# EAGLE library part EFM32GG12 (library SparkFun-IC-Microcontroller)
SiLabs EFM32GG12 Energy efficient MCU. Used as a Segger debugger chip on some products. 93 GPIO pins 32-bit ARM Cortex-M4 processor 1MB Flash memory 192kB internal RAM Datasheet

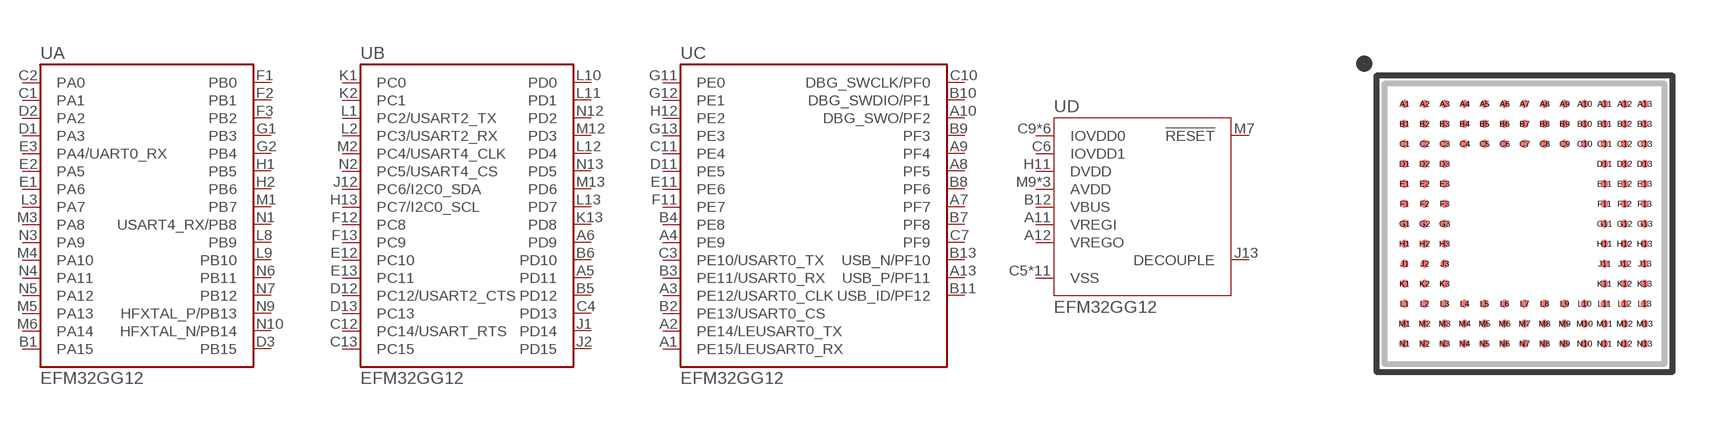
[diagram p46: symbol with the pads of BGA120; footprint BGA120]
Designator prefix U; gates A=EFM32GG12_A B=EFM32GG12_B C=EFM32GG12_C D=EFM32GG12_D

## EFM32GG12B410F1024GL120 (PROD_ID: IC-16889)  [BGA120]
A1  C:PE15/LEUSART0_RX
A2  C:PE14/LEUSART0_TX
A3  C:PE12/USART0_CLK
A4  C:PE9
A5  B:PD11
A6  B:PD9
A7  C:PF7
A8  C:PF5
A9  C:PF4
A10  C:DBG_SWO/PF2
A11  D:VREGI
A12  D:VREGO
A13  C:USB_P/PF11
B1  A:PA15
B2  C:PE13/USART0_CS
B3  C:PE11/USART0_RX
B4  C:PE8
B5  B:PD12
B6  B:PD10
B7  C:PF8
B8  C:PF6
B9  C:PF3
B10  C:DBG_SWDIO/PF1
B11  C:USB_ID/PF12
B12  D:VBUS
B13  C:USB_N/PF10
C1  A:PA1
C2  A:PA0
C3  C:PE10/USART0_TX
C4  B:PD13
C5  D:VSS
C6  D:IOVDD1
C7  C:PF9
C8  D:VSS
C9  D:IOVDD0
C10  C:DBG_SWCLK/PF0
C11  C:PE4
C12  B:PC14/USART_RTS
C13  B:PC15
D1  A:PA3
D2  A:PA2
D3  A:PB15
D11  C:PE5
D12  B:PC12/USART2_CTS
D13  B:PC13
E1  A:PA6
E2  A:PA5
E3  A:PA4/UART0_RX
E11  C:PE6
E12  B:PC10
E13  B:PC11
F1  A:PB0
F2  A:PB1
F3  A:PB2
F11  C:PE7
F12  B:PC8
F13  B:PC9
G1  A:PB3
G2  A:PB4
G3  D:IOVDD0
G11  C:PE0
G12  C:PE1
G13  C:PE3
H1  A:PB5
H2  A:PB6
H3  D:VSS
H11  D:DVDD
H12  C:PE2
H13  B:PC7/I2C0_SCL
J1  B:PD14
J2  B:PD15
J3  D:VSS
J11  D:IOVDD0
J12  B:PC6/I2C0_SDA
J13  D:DECOUPLE
K1  B:PC0
K2  B:PC1
K3  D:IOVDD0
K11  D:VSS
K12  D:VSS
K13  B:PD8
L1  B:PC2/USART2_TX
L2  B:PC3/USART2_RX
L3  A:PA7
L4  D:IOVDD0
L5  D:VSS
L6  D:VSS
L7  D:IOVDD0
L8  A:PB9
L9  A:PB10
L10  B:PD0
L11  B:PD1
L12  B:PD4
L13  B:PD7
M1  A:PB7
M2  B:PC4/USART4_CLK
M3  A:PA8
M4  A:PA10
M5  A:PA13
M6  A:PA14
M7  D:!RESET!
M8  D:VSS
M9  D:AVDD
M10  D:AVDD
M11  D:VSS
M12  B:PD3
M13  B:PD6
N1  A:USART4_RX/PB8
N2  B:PC5/USART4_CS
N3  A:PA9
N4  A:PA11
N5  A:PA12
N6  A:PB11
N7  A:PB12
N8  D:VSS
N9  A:HFXTAL_P/PB13
N10  A:HFXTAL_N/PB14
N11  D:AVDD
N12  B:PD2
N13  B:PD5

## Footprint BGA120 (pad centres in mm)
BGA120 Specifications: Pin count: 120 Package size: 7mm x 7mm Pin pitch: 0.5mm Datasheet referenced for footprint
smd 0.2 x 0.2: A1 -3,3; A2 -2.5,3; A3 -2,3; A4 -1.5,3; A5 -1,3; A6 -0.5,3; A7 0,3; A8 0.5,3; A9 1,3; A10 1.5,3; A11 2,3; A12 2.5,3; A13 3,3; B1 -3,2.5; B2 -2.5,2.5; B3 -2,2.5; B4 -1.5,2.5; B5 -1,2.5; B6 -0.5,2.5; B7 0,2.5; B8 0.5,2.5; B9 1,2.5; B10 1.5,2.5; B11 2,2.5; B12 2.5,2.5; B13 3,2.5; C1 -3,2; C2 -2.5,2; C3 -2,2; C4 -1.5,2; C5 -1,2; C6 -0.5,2; C7 0,2; C8 0.5,2; C9 1,2; C10 1.5,2; C11 2,2; C12 2.5,2; C13 3,2; D1 -3,1.5; D2 -2.5,1.5; D3 -2,1.5; D11 2,1.5; D12 2.5,1.5; D13 3,1.5; E1 -3,1; E2 -2.5,1; E3 -2,1; E11 2,1; E12 2.5,1; E13 3,1; F1 -3,0.5; F2 -2.5,0.5; F3 -2,0.5; F11 2,0.5; F12 2.5,0.5; F13 3,0.5; G1 -3,0; G2 -2.5,0; G3 -2,0; G11 2,0; G12 2.5,0; G13 3,0; H1 -3,-0.5; H2 -2.5,-0.5; H3 -2,-0.5; H11 2,-0.5; H12 2.5,-0.5; H13 3,-0.5; J1 -3,-1; J2 -2.5,-1; J3 -2,-1; J11 2,-1; J12 2.5,-1; J13 3,-1; K1 -3,-1.5; K2 -2.5,-1.5; K3 -2,-1.5; K11 2,-1.5; K12 2.5,-1.5; K13 3,-1.5; L1 -3,-2; L2 -2.5,-2; L3 -2,-2; L4 -1.5,-2; L5 -1,-2; L6 -0.5,-2; L7 0,-2; L8 0.5,-2; L9 1,-2; L10 1.5,-2; L11 2,-2; L12 2.5,-2; L13 3,-2; M1 -3,-2.5; M2 -2.5,-2.5; M3 -2,-2.5; M4 -1.5,-2.5; M5 -1,-2.5; M6 -0.5,-2.5; M7 0,-2.5; M8 0.5,-2.5; M9 1,-2.5; M10 1.5,-2.5; M11 2,-2.5; M12 2.5,-2.5; M13 3,-2.5; N1 -3,-3; N2 -2.5,-3; N3 -2,-3; N4 -1.5,-3; N5 -1,-3; N6 -0.5,-3; N7 0,-3; N8 0.5,-3; N9 1,-3; N10 1.5,-3; N11 2,-3; N12 2.5,-3; N13 3,-3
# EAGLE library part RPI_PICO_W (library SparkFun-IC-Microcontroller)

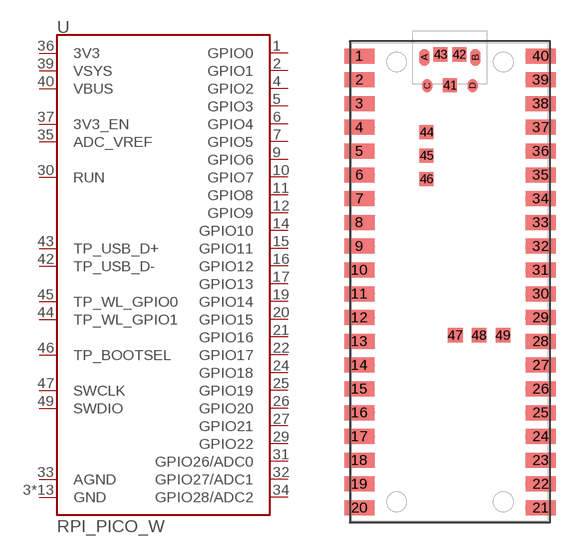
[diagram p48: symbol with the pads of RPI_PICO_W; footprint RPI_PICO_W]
Designator prefix U

## RPI_PICO_W_XRP (PROD_ID: COMP-18042)  [RPI_PICO_W]
1  GPIO0
2  GPIO1
3  GND
4  GPIO2
5  GPIO3
6  GPIO4
7  GPIO5
8  GND
9  GPIO6
10  GPIO7
11  GPIO8
12  GPIO9
13  GND
14  GPIO10
15  GPIO11
16  GPIO12
17  GPIO13
18  GND
19  GPIO14
20  GPIO15
21  GPIO16
22  GPIO17
23  GND
24  GPIO18
25  GPIO19
26  GPIO20
27  GPIO21
28  GND
29  GPIO22
30  RUN
31  GPIO26/ADC0
32  GPIO27/ADC1
33  AGND
34  GPIO28/ADC2
35  ADC_VREF
36  3V3
37  3V3_EN
38  GND
39  VSYS
40  VBUS
41  GND
42  TP_USB_D-
43  TP_USB_D+
44  TP_WL_GPIO1
45  TP_WL_GPIO0
46  TP_BOOTSEL
47  SWCLK
48  GND
49  SWDIO
A  GND
B  GND
C  GND
D  GND

## Footprint RPI_PICO_W (pad centres in mm)
smd 3.2 x 1.6: 1 -9.69,24.13; 2 -9.69,21.59; 3 -9.69,19.05; 4 -9.69,16.51; 5 -9.69,13.97; 6 -9.69,11.43; 7 -9.69,8.89; 8 -9.69,6.35; 9 -9.69,3.81; 10 -9.69,1.27; 11 -9.69,-1.27; 12 -9.69,-3.81; 13 -9.69,-6.35; 14 -9.69,-8.89; 15 -9.69,-11.43; 16 -9.69,-13.97; 17 -9.69,-16.51; 18 -9.69,-19.05; 19 -9.69,-21.59; 20 -9.69,-24.13; 21 9.69,-24.13; 22 9.69,-21.59; 23 9.69,-19.05; 24 9.69,-16.51; 25 9.69,-13.97; 26 9.69,-11.43; 27 9.69,-8.89; 28 9.69,-6.35; 29 9.69,-3.81; 30 9.69,-1.27; 31 9.69,1.27; 32 9.69,3.81; 33 9.69,6.35; 34 9.69,8.89; 35 9.69,11.43; 36 9.69,13.97; 37 9.69,16.51; 38 9.69,19.05; 39 9.69,21.59; 40 9.69,24.13
smd 1.5 x 1.5: 41 0,21; 42 1,24.3; 43 -1,24.3; 44 -2.5,16; 45 -2.5,13.5; 46 -2.5,11
smd 1.575 x 1.575: 47 0.584,-5.7; 48 3.124,-5.7; 49 5.664,-5.7
smd 1.1 x 1.8: A -2.725,24; B 2.725,24
smd 1.05 x 1.45: C -2.425,20.97; D 2.425,20.97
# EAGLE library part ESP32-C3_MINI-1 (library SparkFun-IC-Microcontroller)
Espressif ESP32C3-MINI-1 ESP32-C3-MINI-1 and ESP32-C3-MINI-1U are two general-purpose Wi-Fi and Bluetooth LE modules. The rich set of peripherals and a small size make the two modules an ideal choice for smart homes, industrial automation, health care, consumer electronics, etc. ESP32-C3-MINI-1 comes with a PCB antenna. ESP32-C3-MINI-1U comes with an external antenna connector. A wide selection of module variants are available as shown in Table 1 and 2. The series comparison for the two modules is as follows:

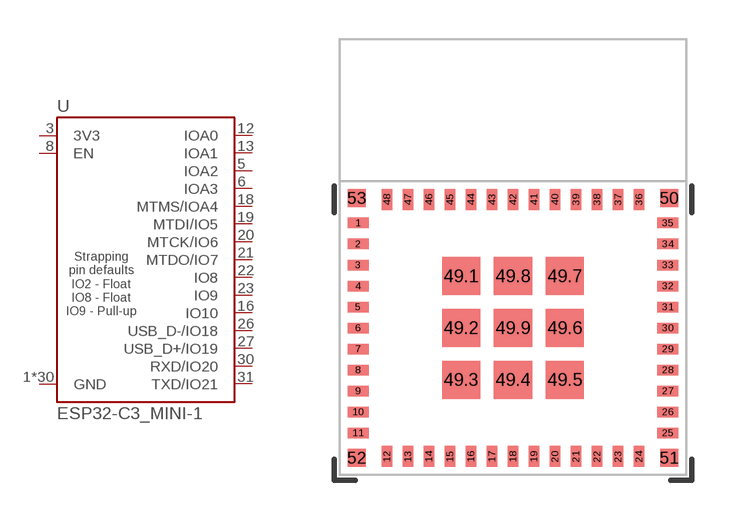
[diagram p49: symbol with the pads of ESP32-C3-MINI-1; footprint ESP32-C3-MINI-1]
Designator prefix U

## ESP32-C3_MINI-1 (PROD_ID: IC-20056)  [ESP32-C3-MINI-1]
1  GND
2  GND
3  3V3
5  IOA2
6  IOA3
8  EN
11  GND
12  IOA0
13  IOA1
14  GND
16  IO10
18  MTMS/IOA4
19  MTDI/IO5
20  MTCK/IO6
21  MTDO/IO7
22  IO8
23  IO9
26  USB_D-/IO18
27  USB_D+/IO19
30  RXD/IO20
31  TXD/IO21
36  GND
37  GND
38  GND
39  GND
40  GND
41  GND
42  GND
43  GND
44  GND
45  GND
46  GND
47  GND
48  GND
49.1  GND
49.2  GND
49.3  GND
49.4  GND
49.5  GND
49.6  GND
49.7  GND
49.8  GND
49.9  GND
50  GND
51  GND
52  GND
53  GND

## Footprint ESP32-C3-MINI-1 (pad centres in mm)
smd 0.8 x 0.4: 1 -5.9,4; 2 -5.9,3.2; 3 -5.9,2.4; 4 -5.9,1.6; 5 -5.9,0.8; 6 -5.9,0; 7 -5.9,-0.8; 8 -5.9,-1.6; 9 -5.9,-2.4; 10 -5.9,-3.2; 11 -5.9,-4; 25 5.9,-4; 26 5.9,-3.2; 27 5.9,-2.4; 28 5.9,-1.6; 29 5.9,-0.8; 30 5.9,0; 31 5.9,0.8; 32 5.9,1.6; 33 5.9,2.4; 34 5.9,3.2; 35 5.9,4
smd 0.4 x 0.8: 12 -4.8,-4.9; 13 -4,-4.9; 14 -3.2,-4.9; 15 -2.4,-4.9; 16 -1.6,-4.9; 17 -0.8,-4.9; 18 0,-4.9; 19 0.8,-4.9; 20 1.6,-4.9; 21 2.4,-4.9; 22 3.2,-4.9; 23 4,-4.9; 24 4.8,-4.9; 36 4.8,4.9; 37 4,4.9; 38 3.2,4.9; 39 2.4,4.9; 40 1.6,4.9; 41 0.8,4.9; 42 0,4.9; 43 -0.8,4.9; 44 -1.6,4.9; 45 -2.4,4.9; 46 -3.2,4.9; 47 -4,4.9; 48 -4.8,4.9
smd 1.45 x 1.45: 49.1 -1.975,1.975; 49.2 -1.975,0; 49.3 -1.975,-1.975; 49.4 0,-1.975; 49.5 1.975,-1.975; 49.6 1.975,0; 49.7 1.975,1.975; 49.8 0,1.975; 49.9 0,0
smd 0.7 x 0.7: 50 5.95,4.95; 51 5.95,-4.95; 52 -5.95,-4.95; 53 -5.95,4.95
